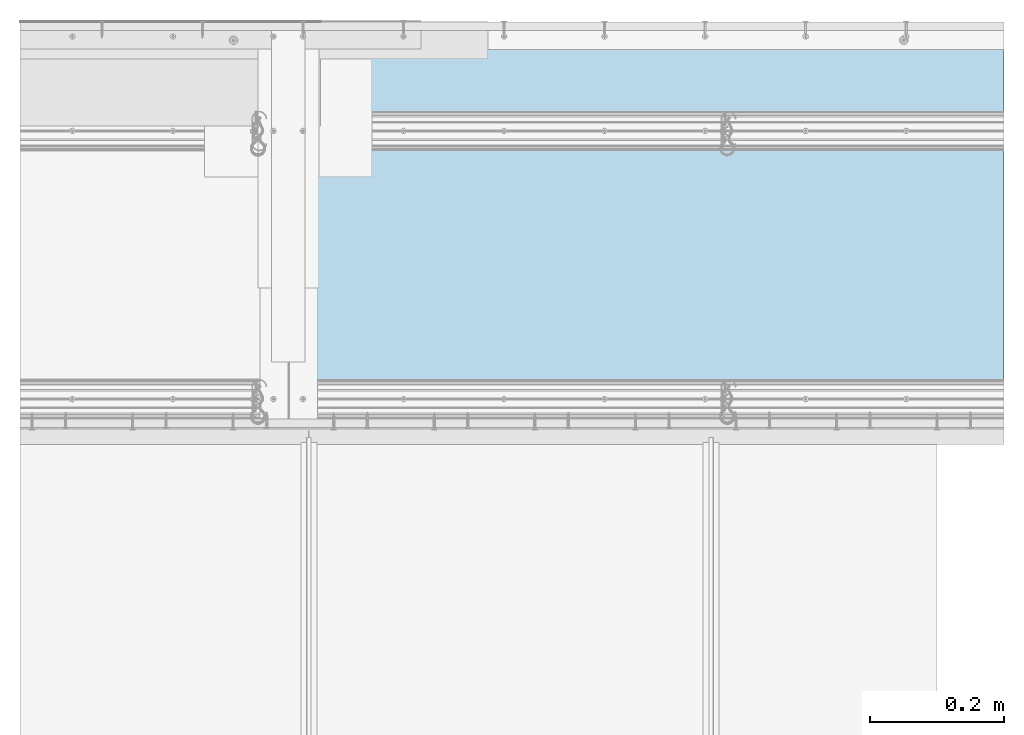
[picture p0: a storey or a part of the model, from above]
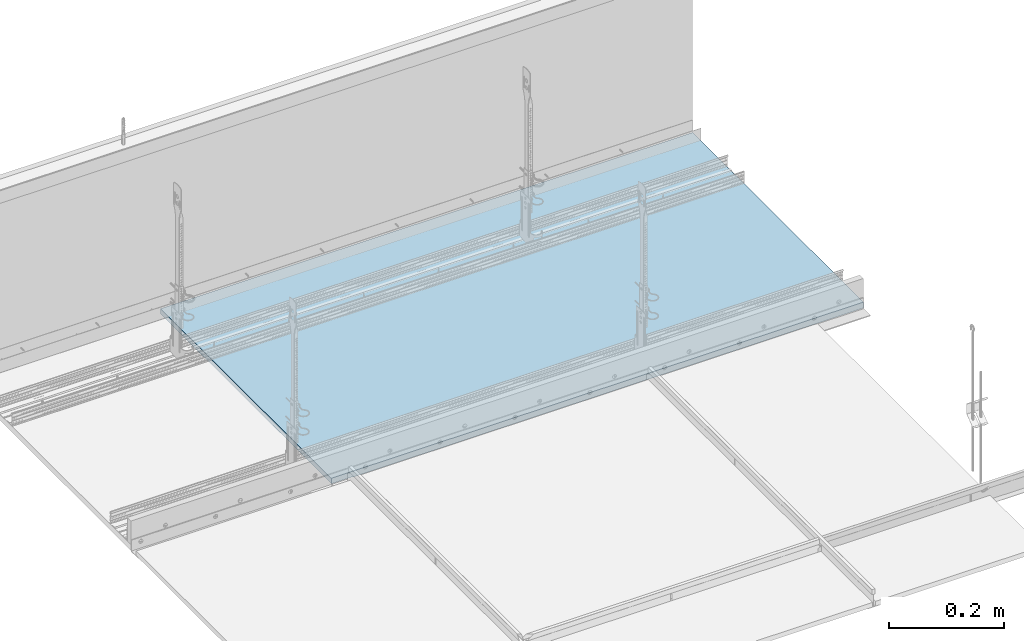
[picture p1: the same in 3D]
Properties of the parts of a building model (IFC2X3)

# File
Description: ViewDefinition [CoordinationView]
Time: 2022-02-03T10:34:29
Made in: SketchUp Pro 2015

# IfcProject, Default Project
Description: Description of Default Project

# IfcSite, Default Site
Description: Description of Default Site; RefLatitude: 24, 28, 0; RefLongitude: 54, 25, 0; RefElevation: 10 mm

# IfcBuilding, Default Building
Description: Description of Default Building

# IfcBuildingStorey, Default Building Storey
In: Default Building
Description: Description of Default Building Storey; Elevation: 0 mm

# IfcBuildingElementProxy, Profil poprzeczny RIGIPS T24
In: Default Building Storey
Description: Description of Object

# IfcSlab (117)
In: Default Building Storey
Description: Description of Object
PredefinedType - IfcSlabTypeEnum: floor
Name
4 x Płyta gipsowo-kartonowa RIGIPS PRO (4PRO™)
Dedykowana masa szpachlowa Rigips - wykończeniowa
Taśma spoinowa RIGIPS
2 x Dedykowana masa szpachlowa Rigips - konstrukcyjna
6 x Płyta sufitowa RIGIPS CASOPRANO
4 x Profil poprzeczny RIGIPS T24
58 x Wkręt RIGIPS TN 25
2 x Pręt wieszakowy z oczkiem | TempShadowInfo - City: Boulder (CO); Country: USA; Latitude: 40.017; Longitude: 40.017-105.283; NorthAngle: 40.017-105.2830; TZOffset: 40.017-105.2830-7
2 x Wieszak z podwójnym elementem rozprężnym | TempShadowInfo - City: Boulder (CO); Country: USA; Latitude: 40.017; Longitude: 40.017-105.283; NorthAngle: 40.017-105.2830; TZOffset: 40.017-105.2830-7
2 x Pręt wieszakowy z hakiem
4 x Stalowy element mocujący
Taśma uszczelniająca piankowa RIGIPS
2 x Profil RIGIPS UD 30 ULTRASTIL®
4 x Wieszak obrotowy RIGIPS noniuszowy
8 x Klamra zabezpieczająca do wieszaków noniuszowych
4 x Część górna wieszaka noniuszowego
2 x Profil RIGIPS CD 60 ULTRASTIL®
10 x Łącznik mechaniczny

# IfcWall (5)
In: Default Building Storey
Description: Description of Object
Name
Kątownik
Dedykowana masa szpachlowa Rigips - konstrukcyjna
2 x Dedykowana masa szpachlowa Rigips - wykończeniowa
Taśma narożnikowa HABITO® NO-COAT® | dynamic_attributes - _has_movetool_behaviors: 0; _lengthunits: CENTIMETERS; _name: Taśma narożnikowa HABITO® NOCOAT®; _formatversion: 1; _lastmodified: 2021-12-02 11:34; IfcPropertySet - _last_lenx: 01.69291; _last_leny: 01.692911.69291; _last_lenz: 01.692911.6929123.5571
